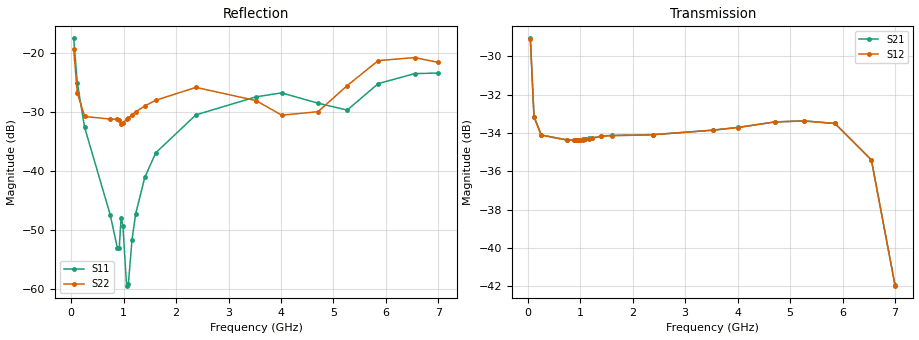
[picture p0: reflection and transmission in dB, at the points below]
! Integrated Device Technology
! Corporate Headquarters
! 6024 Silver Creek Valley Road
! San Jose, CA 95138  USA
! Phone:  1-408-284-8200
! Toll Free:  1-800-223-1366
! Webpage:  http://www.idt.com/
! Timing and RF Division
! 515 Groton Road, Suite 102
! Westford, MA 01886-6024
! Device:  F2258
! Description: Voltage Variable RF Attenuator
! Frequency:  50.0 -  6000.00 MHz
! Package:  3x3 mm Thin QFN Plastic Package: 16 pin
! Ports:  2 RF, 2 DC
!  Pin  1  = NC
!  Pin  2  = NC
!  Pin  3  = RF2  = Port 2
!  Pin  4  = GND
!  Pin  5  = Vdd
!  Pin  6  = NC
!  Pin  7  = VCTRL
!  Pin  8  = NC
!  Pin  9  = GND
!  Pin 10  = RF1  = Port 1
!  Pin 11  = NC
!  Pin 12  = NC
!  Pin 13  = NC
!  Pin 14  = NC
!  Pin 15  = NC
!  Pin 16  = NC
! Vcntrl:  1.880 Volts
! Vdd:  +3.300 Volts
! Current:  1.156 mA
! Data:  The device was measured on a the F2258 evaluation board which has
!  individual transmission lines to the RF pins.  Data was collected
!  using a calibrated network analyzer.  The evaluation board was
!  de-embedded using a TRL calibration technique.
!  The reference plane is the edge of the package pin.
! Misc:  SN 10
!  Action Tracker AT0285
! Date Measured:  2014-12-10
! Date:  2016-01-13  MJV
! Note:
!  Integrated Device Technology supplies this data as a sample of measured
!  data at the package pin for this product.  Your particular data for this
!  product may vary.
!  Data was taken at 25 degrees C.
!  Integrated Device Technology reserves the right to change this data at anytime.
!Freq_(GHz)  S11M_(dB)  S11P_(deg)  S21M_(dB)  S21P_(deg)  S12M_(dB)  S12P_(deg)  S22M_(dB)  S22P_(deg)
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# GHz S dB R 50
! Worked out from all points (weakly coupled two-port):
!   201 points, 50 MHz to 7 GHz, reference 50 ohm
!   highest |S21| = -29.06 dB at 50 MHz (marker M1); lowest = -42.0 dB at 7 GHz (marker M2)
!   lowest |S11| = -59.4 dB at 1.058 GHz (marker M3), VSWR 1.00, Z = 49.9 + j0.0463 ohm
!   |S11| at or under -10 dB: start of sweep to end of sweep
!   |S22| runs from -32.1 to -19.4 dB; largest |S21 - S12| = 6.5e-05
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0.05  -17.55 -110.8  -29.06 -64.1  -29.07 -64.1  -19.38 -102.4
0.1195  -25.11 -106.6  -33.15 -34.0  -33.16 -34.0  -26.83 -71.3
0.2585  -32.62 -111.2  -34.10 -17.6  -34.11 -17.6  -30.77 -37.2
0.745  -47.39 -141.1  -34.35 -9.4  -34.37 -9.3  -31.22 -3.0
0.884  -53.11 166.7  -34.35 -9.0  -34.37 -9.0  -31.24 -1.1
0.91875  -53.01 148.5  -34.35 -9.0  -34.37 -9.0  -31.30 -0.7
0.9535  -47.89 -160.7  -34.36 -8.9  -34.38 -8.9  -32.09 4.5
0.98825  -49.31 -172.2  -34.35 -8.9  -34.36 -8.9  -31.92 3.4
1.05775  -59.43 154.2  -34.33 -8.8  -34.34 -8.8  -31.22 4.1
1.0925  -59.06 111.6  -34.31 -8.8  -34.33 -8.8  -31.05 4.2
1.162  -51.62 65.2  -34.28 -8.9  -34.31 -8.9  -30.50 4.4
1.2315  -47.25 43.4  -34.25 -9.0  -34.27 -9.0  -30.00 4.4
1.40525  -41.08 32.3  -34.15 -9.8  -34.16 -9.8  -28.99 5.6
1.61375  -36.93 31.8  -34.12 -11.0  -34.14 -11.0  -28.03 4.4
2.37825  -30.51 47.6  -34.08 -15.2  -34.09 -15.2  -25.85 7.0
3.525  -27.45 91.4  -33.85 -22.4  -33.85 -22.4  -28.09 26.0
4.0115  -26.78 104.4  -33.70 -26.2  -33.71 -26.2  -30.55 33.3
4.7065  -28.53 95.5  -33.42 -31.9  -33.42 -32.0  -29.97 13.3
5.2625  -29.69 53.9  -33.36 -38.1  -33.37 -38.1  -25.54 -12.0
5.85325  -25.21 29.6  -33.50 -48.2  -33.50 -48.2  -21.32 -22.2
6.54825  -23.52 44.9  -35.40 -67.3  -35.40 -67.4  -20.80 -53.1
7  -23.42 84.3  -41.95 -64.1  -41.96 -63.7  -21.63 -125.4
